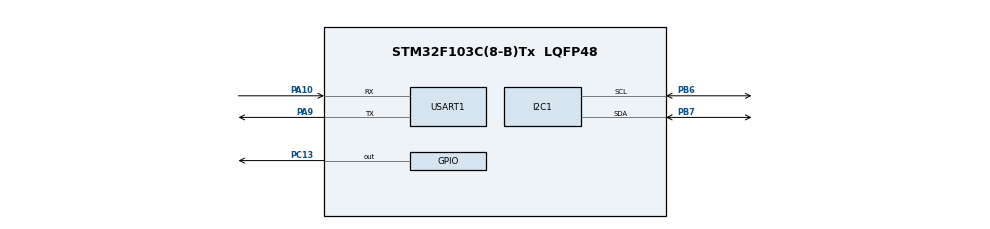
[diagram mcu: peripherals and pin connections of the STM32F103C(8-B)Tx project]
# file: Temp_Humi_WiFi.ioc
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Mcu.Family=STM32F1
Mcu.Name=STM32F103C(8-B)Tx
Mcu.Package=LQFP48
NVIC.PriorityGroup=NVIC_PRIORITYGROUP_4
PA10.Mode=Asynchronous
PA10.Signal=USART1_RX
PA13.Mode=Serial_Wire
PA13.Signal=SYS_JTMS-SWDIO
PA14.Mode=Serial_Wire
PA14.Signal=SYS_JTCK-SWCLK
PA9.Mode=Asynchronous
PA9.Signal=USART1_TX
PB6.Mode=I2C
PB6.Signal=I2C1_SCL
PB7.Mode=I2C
PB7.Signal=I2C1_SDA
PC13-TAMPER-RTC.PinState=GPIO_PIN_SET
PC13-TAMPER-RTC.Signal=GPIO_Output
PD0-OSC_IN.Mode=HSE-External-Oscillator
PD0-OSC_IN.Signal=RCC_OSC_IN
PD1-OSC_OUT.Mode=HSE-External-Oscillator
PD1-OSC_OUT.Signal=RCC_OSC_OUT
ProjectManager.HeapSize=0x200
ProjectManager.StackSize=0x400
ProjectManager.TargetToolchain=MDK-ARM V5
RCC.AHBFreq_Value=72000000
RCC.APB1Freq_Value=72000000
RCC.APB1TimFreq_Value=72000000
RCC.APB2Freq_Value=72000000
RCC.APB2TimFreq_Value=72000000
RCC.HCLKFreq_Value=72000000
RCC.PLLMUL=RCC_PLL_MUL9
RCC.PLLSourceVirtual=RCC_PLLSOURCE_HSE
RCC.SYSCLKFreq_VALUE=72000000
RCC.SYSCLKSource=RCC_SYSCLKSOURCE_PLLCLK
RCC.USBFreq_Value=72000000
USART1.VirtualMode=VM_ASYNC
board=custom

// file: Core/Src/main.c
/* USER CODE BEGIN Header */
/**
  ******************************************************************************
  * @file           : main.c
  * @brief          : Main program body
  ******************************************************************************
  * @attention
  *
  * Copyright (c) 2026 STMicroelectronics.
  * All rights reserved.
  *
  * This software is licensed under terms that can be found in the LICENSE file
  * in the root directory of this software component.
  * If no LICENSE file comes with this software, it is provided AS-IS.
  *
  ******************************************************************************
  */
/* USER CODE END Header */
#include "main.h"

/* USER CODE BEGIN Includes */

#include"sht30.h"
#include"oled.h"
#include"esp8266.h"
#include<stdio.h>

/* USER CODE END Includes */

I2C_HandleTypeDef hi2c1;

UART_HandleTypeDef huart1;

/* USER CODE BEGIN PV */

uint8_t esp_rx_buf[512];
SHT30_Data sht30_data;

/* ===== WiFi 配置 ===== */
/* 真实 WiFi 名/密码/电脑 IP 不入库（防泄露），在 Core/Inc/wifi_real.h 里配置，
 * 仓库里只有模板 wifi_real_template.h，克隆后复制改名为 wifi_real.h 即可 */
#include "wifi_real.h"

/* USER CODE END PV */

void SystemClock_Config(void);
static void MX_GPIO_Init(void);
static void MX_I2C1_Init(void);
static void MX_USART1_UART_Init(void);

/* USER CODE BEGIN 0 */

/* PC13 LED 闪烁 N 次（蓝板低电平亮）
 * 用途：ESP8266 各阶段状态编码
 *   闪1次 = AT 测试通过
 *   闪2次 = WiFi 连接成功
 *   持续快闪 = 某步失败
 */
static void led_blink(uint8_t times)
{
    for (uint8_t i = 0; i < times; i++) {
        HAL_GPIO_WritePin(GPIOC, GPIO_PIN_13, GPIO_PIN_RESET);  /* 亮 */
        HAL_Delay(200);
        HAL_GPIO_WritePin(GPIOC, GPIO_PIN_13, GPIO_PIN_SET);    /* 灭 */
        HAL_Delay(200);
    }
}

/* 失败时一直快闪，用来卡住程序提醒用户 */
static void led_fail(void)
{
    while (1) {
        HAL_GPIO_WritePin(GPIOC, GPIO_PIN_13, GPIO_PIN_RESET);
        HAL_Delay(100);
        HAL_GPIO_WritePin(GPIOC, GPIO_PIN_13, GPIO_PIN_SET);
        HAL_Delay(100);
    }
}

/* USER CODE END 0 */

int main(void)
{

  /* MCU Configuration--------------------------------------------------------*/

  /* Reset of all peripherals, Initializes the Flash interface and the Systick. */
  HAL_Init();

  /* Configure the system clock */
  SystemClock_Config();

  /* Initialize all configured peripherals */
  MX_GPIO_Init();
  MX_I2C1_Init();
  MX_USART1_UART_Init();
  /* USER CODE BEGIN 2 */

/* ===== 第1步：OLED + SHT30 初始化 ===== */
OLED_Init();
OLED_ShowCenter("Temp & Humi", "System OK");

SHT30_Init();

/* ===== 第2步：ESP8266 初始化 + AT 测试 ===== */
ESP8266_Init(esp_rx_buf, sizeof(esp_rx_buf));

if (ESP8266_ATTest()) {
    led_blink(1);              /* 闪1次 = AT 通信正常 */
} else {
    OLED_ShowCenter("ESP8266", "AT Error!");
    led_fail();                /* 一直快闪 = AT 无响应，检查接线 */
}

/* ===== 第3步：连接 WiFi ===== */
OLED_ShowCenter("Connecting", "WiFi...");
if (ESP8266_ConnectWiFi(WIFI_SSID, WIFI_PASSWORD)) {
    led_blink(2);              /* 闪2次 = WiFi 连上 */
    OLED_ShowCenter("WiFi OK!", "Reading...");
    HAL_Delay(1000);           /* 等1秒让供电稳定再读SHT30 */
} else {
    OLED_ShowCenter("WiFi", "Failed!");
    led_fail();                /* 一直快闪 = WiFi 连接失败 */
}

/* ===== 第3.5步：联网实测（TCP+HTTP 连公网 www.baidu.com） ===== */
if (ESP8266_NetTest()) {
    led_blink(3);              /* 闪3次 = 真正联网成功 */
    OLED_ShowCenter("Internet", "OK!");
} else {
    OLED_ShowCenter("Net", "Test Failed!");
}
HAL_Delay(2000);               /* 停2秒让用户看清联网测试结果 */

/* ===== 第4步：主循环 —— 读温湿度 + 显示 + 上传电脑 ===== */
/* PC_IP / PC_PORT 已移到 wifi_real.h：改电脑IP后只改那个文件，不用动 main.c */

uint8_t upload_cnt = 0;
while (1) {
    SHT30_Data data;
    uint8_t sht_ok = 0;

    /* 最多重试3次：ESP8266 WiFi 可能拉低电压导致 I2C 偶发失败 */
    for (uint8_t retry = 0; retry < 3; retry++) {
        if (SHT30_Read(&data) == 1) {
            sht_ok = 1;
            break;
        }
        /* I2C 出错需复位外设，否则后续所有 I2C 通信全部失败 */
        HAL_I2C_DeInit(&hi2c1);
        HAL_I2C_Init(&hi2c1);
        HAL_Delay(50);
    }

    if (sht_ok) {
        OLED_ShowData(data.temperature, data.humidity);

        /* 每 3 次循环（约6秒）上传一次到电脑，避免TCP连接太频繁 */
        if (++upload_cnt >= 3) {
            upload_cnt = 0;
            if (ESP8266_SendData(PC_IP, PC_PORT, data.temperature, data.humidity)) {
                OLED_ShowCenter("Upload", "OK!");
            } else {
                OLED_ShowCenter("Upload", "Failed!");
            }
            HAL_Delay(1000);   /* 停1秒让用户看清上传结果 */
        }
    } else {
        /* I2C 复位后 OLED 也需要重新初始化，否则黑屏 */
        OLED_Init();
        OLED_ShowCenter("SHT30 Error", "Check I2C!");
        HAL_GPIO_WritePin(GPIOC, GPIO_PIN_13, GPIO_PIN_RESET);
        HAL_Delay(200);
        HAL_GPIO_WritePin(GPIOC, GPIO_PIN_13, GPIO_PIN_SET);
    }
    HAL_Delay(2000);                      /* 每 2 秒刷新一次 */
}
/* USER CODE END 2 */

  /* Infinite loop */
  while (1)
  {

    /* USER CODE BEGIN 3 */
    HAL_Delay(1000);  /* 扫描调试期间什么都不做 */
    /* USER CODE END 3 */
  }
}  /* 关闭 main() */

void SystemClock_Config(void)
{
  RCC_OscInitTypeDef RCC_OscInitStruct = {0};
  RCC_ClkInitTypeDef RCC_ClkInitStruct = {0};

  /** Initializes the RCC Oscillators according to the specified parameters
  * in the RCC_OscInitTypeDef structure.
  */
  RCC_OscInitStruct.OscillatorType = RCC_OSCILLATORTYPE_HSE;
  RCC_OscInitStruct.HSEState = RCC_HSE_ON;
  RCC_OscInitStruct.HSEPredivValue = RCC_HSE_PREDIV_DIV1;
  RCC_OscInitStruct.HSIState = RCC_HSI_ON;
  RCC_OscInitStruct.PLL.PLLState = RCC_PLL_ON;
  RCC_OscInitStruct.PLL.PLLSource = RCC_PLLSOURCE_HSE;
  RCC_OscInitStruct.PLL.PLLMUL = RCC_PLL_MUL9;
  if (HAL_RCC_OscConfig(&RCC_OscInitStruct) != HAL_OK)
  {
    Error_Handler();
  }

  /** Initializes the CPU, AHB and APB buses clocks
  */
  RCC_ClkInitStruct.ClockType = RCC_CLOCKTYPE_HCLK|RCC_CLOCKTYPE_SYSCLK
                              |RCC_CLOCKTYPE_PCLK1|RCC_CLOCKTYPE_PCLK2;
  RCC_ClkInitStruct.SYSCLKSource = RCC_SYSCLKSOURCE_PLLCLK;
  RCC_ClkInitStruct.AHBCLKDivider = RCC_SYSCLK_DIV1;
  RCC_ClkInitStruct.APB1CLKDivider = RCC_HCLK_DIV2;  /* APB1 必须 /2 = 36MHz，F103 上限，I2C1 挂在 APB1 上 */
  RCC_ClkInitStruct.APB2CLKDivider = RCC_HCLK_DIV1;

  if (HAL_RCC_ClockConfig(&RCC_ClkInitStruct, FLASH_LATENCY_2) != HAL_OK)
  {
    Error_Handler();
  }
}

static void MX_I2C1_Init(void)
{

  hi2c1.Instance = I2C1;
  hi2c1.Init.ClockSpeed = 100000;
  hi2c1.Init.DutyCycle = I2C_DUTYCYCLE_2;
  hi2c1.Init.OwnAddress1 = 0;
  hi2c1.Init.AddressingMode = I2C_ADDRESSINGMODE_7BIT;
  hi2c1.Init.DualAddressMode = I2C_DUALADDRESS_DISABLE;
  hi2c1.Init.OwnAddress2 = 0;
  hi2c1.Init.GeneralCallMode = I2C_GENERALCALL_DISABLE;
  hi2c1.Init.NoStretchMode = I2C_NOSTRETCH_DISABLE;
  if (HAL_I2C_Init(&hi2c1) != HAL_OK)
  {
    Error_Handler();
  }

}

static void MX_USART1_UART_Init(void)
{

  huart1.Instance = USART1;
  huart1.Init.BaudRate = 115200;
  huart1.Init.WordLength = UART_WORDLENGTH_8B;
  huart1.Init.StopBits = UART_STOPBITS_1;
  huart1.Init.Parity = UART_PARITY_NONE;
  huart1.Init.Mode = UART_MODE_TX_RX;
  huart1.Init.HwFlowCtl = UART_HWCONTROL_NONE;
  huart1.Init.OverSampling = UART_OVERSAMPLING_16;
  if (HAL_UART_Init(&huart1) != HAL_OK)
  {
    Error_Handler();
  }

}

static void MX_GPIO_Init(void)
{
  GPIO_InitTypeDef GPIO_InitStruct = {0};

  /* GPIO Ports Clock Enable */
  __HAL_RCC_GPIOC_CLK_ENABLE();
  __HAL_RCC_GPIOD_CLK_ENABLE();
  __HAL_RCC_GPIOA_CLK_ENABLE();
  __HAL_RCC_GPIOB_CLK_ENABLE();

  /*Configure GPIO pin Output Level */
  HAL_GPIO_WritePin(GPIOC, GPIO_PIN_13, GPIO_PIN_SET);

  /*Configure GPIO pin : PC13 */
  GPIO_InitStruct.Pin = GPIO_PIN_13;
  GPIO_InitStruct.Mode = GPIO_MODE_OUTPUT_PP;
  GPIO_InitStruct.Pull = GPIO_NOPULL;
  GPIO_InitStruct.Speed = GPIO_SPEED_FREQ_LOW;
  HAL_GPIO_Init(GPIOC, &GPIO_InitStruct);

}

void Error_Handler(void)
{
  __disable_irq();
  while (1)
  {
  }
}
